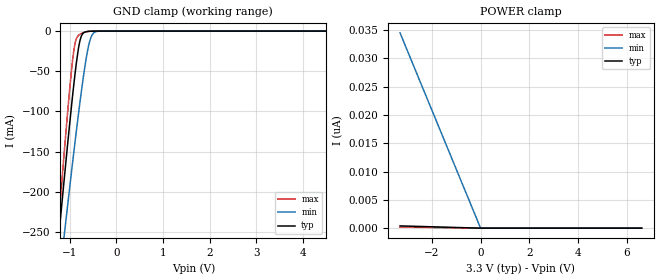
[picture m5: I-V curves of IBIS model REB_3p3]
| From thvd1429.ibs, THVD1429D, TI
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|   REB_3p3 Model
[Model]   REB_3p3
Model_type   Input
Vinl = 0.8
Vinh = 2
|   typ   min   max
C_comp   3.662pF   3.174pF   4.146pF
| Where Nom  PVT is Nominal Process, 3.3V, 25C
|   Fast PVT is Strong Process,  3.6V, -40C
|   Slow PVT is Weak Process,   3.0V, 150C
[Voltage Range]   3.3   3   3.6
|Junction Temperature
[Temperature Range]   25   150   -40
[Power Clamp Reference]   3.3   3   3.6
[GND Clamp Reference]   0   0   0
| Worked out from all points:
|   GND clamp passes 1 mA (typ) near -0.66 V on its own axis
[GND Clamp]
|   Voltage   I(typ)   I(min)   I(max)
-3.3V     -1.586A    -1.429A    -1.817A
-1.379V   -345.3mA   -390.1mA   -341.4mA
-1.221V   -246.5mA   -307.1mA   -224.3mA
-1.112V   -180.1mA   -250.8mA   -146.3mA
-993.3mV  -110.3mA   -190.5mA   -66.91mA
-914.1mV  -66.85mA   -151.2mA   -24.69mA
-874.5mV  -47.04mA   -132mA     -12.26mA
-815.1mV  -21.99mA   -103.9mA   -5.44mA
-726mV    -3.556mA   -64.31mA   -2.32mA
-567.6mV  -217.4uA   -11.67mA   -218.3uA
-399.3mV  -10.3uA    -273.4uA   -6.968uA
6.6V      0A         0A         0A
[POWER Clamp]
|   Voltage   I(typ)   I(min)   I(max)
-3.3V     400.5pA    34.52nA    192pA
0V        0A         0A         0A
6.6V      0A         0A         0A
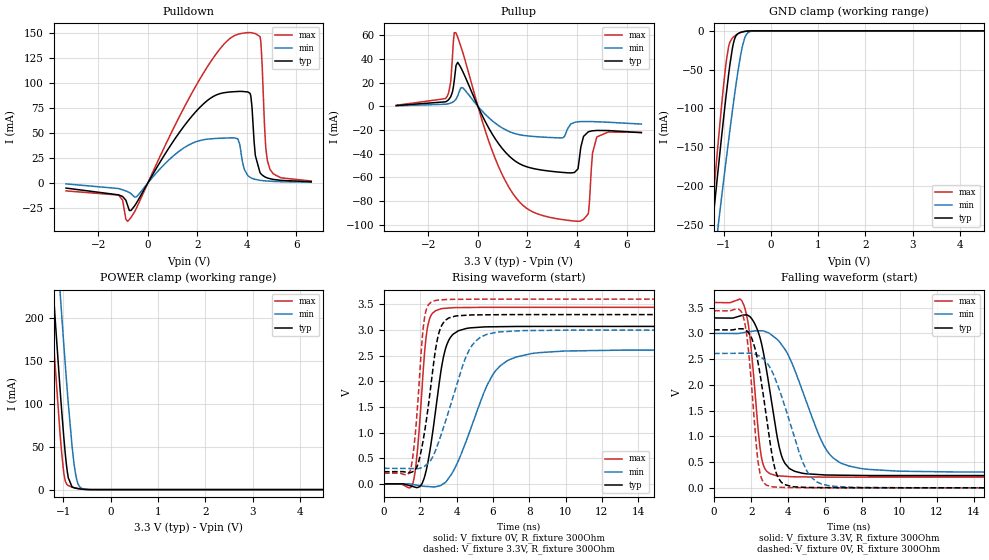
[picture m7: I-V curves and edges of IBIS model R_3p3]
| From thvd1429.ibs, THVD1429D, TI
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|   R_3p3 Model
[Model]   R_3p3
Model_type   3-state
Polarity   Non-Inverting
Vmeas = 1.65
Vref = 0
Cref = 2pF
Rref = 100000
|   typ   min   max
C_comp   4.739pF   4.609pF   4.805pF
| Where Nom  PVT is Nominal Process, 3.3V, 25C
|   Fast PVT is Strong Process,  3.6V, -40C
|   Slow PVT is Weak Process,   3.0V, 150C
[Voltage Range]   3.3   3   3.6
|Junction Temperature
[Temperature Range]   25   150   -40
[Pullup Reference]   3.3   3   3.6
[Pulldown Reference]   0   0   0
[Power Clamp Reference]   3.3   3   3.6
[GND Clamp Reference]   0   0   0
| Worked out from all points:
|   slope of the pulldown table from 0 to 0.495 V, typ, clamps not added: 23.7 ohm
|   slope of the pullup table from 0 to 0.495 V, typ, clamps not added: 24.1 ohm
|   GND clamp passes 1 mA (typ) near -0.58 V on its own axis
|   POWER clamp passes 1 mA (typ) near -0.67 V on its own axis
|   falling waveform, V_fixture 3.3V, R_fixture 300Ohm: 20-80 % time 853ps typ, 1.74ns min, 506ps max; typ from 3.3 V to 0.237 V
|   rising waveform, V_fixture 0V, R_fixture 300Ohm: 20-80 % time 751ps typ, 1.75ns min, 436ps max; typ from 0 V to 3.07 V
|   rising waveform, V_fixture 3.3V, R_fixture 300Ohm: 20-80 % time 714ps typ, 1.46ns min, 427ps max; typ from 0.237 V to 3.3 V
|   falling waveform, V_fixture 0V, R_fixture 300Ohm: 20-80 % time 781ps typ, 1.43ns min, 484ps max; typ from 3.07 V to 0 V
[Pulldown]
|   Voltage   I(typ)   I(min)   I(max)
-3.3V     -5.004mA   -808.9uA   -7.788mA
-1.191V   -11.72mA   -5.429mA   -11.96mA
-815.1mV  -22.29mA   -8.553mA   -38.1mA
2.373V    81.63mA    43.65mA    114.7mA
3.62V     91.29mA    44.25mA    148.2mA
4.046V    90.8mA     7.35mA     150mA
4.165V    85.92mA    5.258mA    149.9mA
4.343V    27.4mA     3.665mA    149mA
4.541V    10.13mA    2.745mA    145mA
4.759V    5.819mA    2.159mA    37.1mA
4.927V    4.383mA    1.859mA    14.12mA
6.6V      1.371mA    840.4uA    2.04mA
[GND Clamp]
|   Voltage   I(typ)   I(min)   I(max)
-3.3V     -1.553A    -1.424A    -1.755A
-1.379V   -339.1mA   -389.3mA   -331.1mA
-1.221V   -242.6mA   -306.6mA   -218.2mA
-1.112V   -177.7mA   -250.6mA   -143mA
-993.3mV  -109.4mA   -190.5mA   -66.79mA
-894.3mV  -57.17mA   -141.8mA   -20.64mA
-815.1mV  -23.4mA    -104.4mA   -9.505mA
-775.5mV  -12.37mA   -86.35mA   -7.293mA
-646.8mV  -2.133mA   -34.28mA   -2.531mA
-528mV    -536.6uA   -5.945mA   -570.7uA
-359.7mV  -25.1uA    -169uA     -14.98uA
6.6V      0A         0A         0A
[Pullup]
|   Voltage   I(typ)   I(min)   I(max)
-3.3V     632.8uA    409.7uA    833.3uA
-1.29V    4.001mA    1.824mA    6.974mA
-1.102V   7.96mA     2.751mA    20.36mA
-953.7mV  22.11mA    4.47mA     62.39mA
-884.4mV  34.56mA    6.104mA    62.1mA
-617.1mV  29.65mA    15.65mA    45.87mA
1.264V    -42.14mA   -21.34mA   -68.96mA
3.897V    -56.01mA   -13.6mA    -97.09mA
4.452V    -21.69mA   -12.87mA   -91.02mA
4.63V     -20.73mA   -12.96mA   -39.26mA
4.808V    -20.42mA   -13.08mA   -25.87mA
6.6V      -22.29mA   -15.03mA   -22.07mA
[POWER Clamp]
|   Voltage   I(typ)   I(min)   I(max)
-3.3V     2.079A     2.185A     2.031A
-1.449V   432.3mA    547.8mA    378.6mA
-1.251V   263.9mA    379.9mA    209.6mA
-1.221V   239.2mA    355.2mA    184.9mA
-1.191V   214.8mA    330.6mA    160.5mA
-1.063V   113mA      226.2mA    61.48mA
-983.4mV  57.32mA    164.8mA    17.27mA
-894.3mV  13.78mA    100.3mA    4.716mA
-805.2mV  2.832mA    45.77mA    2.883mA
-735.9mV  1.584mA    16.99mA    1.897mA
-567.6mV  338.4uA    707.4uA    328uA
6.6V      0A         0A         0A
[Ramp]
R_load = 300
|   typ   min   max
dV/dt_r   1.84126/7.51035e-10   1.56567/1.74295e-09   2.06375/4.34792e-10
dV/dt_f   1.83723/8.51106e-10   1.6172/1.73394e-09   2.0352/5.05101e-10
[Falling Waveform]
V_fixture = 3.3V
V_fixture_min = 3V
V_fixture_max = 3.6V
R_fixture = 300Ohm
C_fixture = 0F
|   Time   V(typ)   V(min)   V(max)
0s        3.3V       3V         3.599V
1.607ns   3.356V     3.015V     3.548V
1.939ns   3.323V     3.034V     2.915V
2.546ns   2.819V     3.052V     610.5mV
3.307ns   1.201V     2.911V     242.5mV
3.664ns   596.3mV    2.769V     229.1mV
4.097ns   368mV      2.502V     218.9mV
6.083ns   249.7mV    722.2mV    208.6mV
7.879ns   241.6mV    379mV      208.6mV
50ns      237.5mV    304.3mV    207.4mV
[Rising Waveform]
V_fixture = 0V
V_fixture_min = 0V
V_fixture_max = 0V
R_fixture = 300Ohm
C_fixture = 0F
|   Time   V(typ)   V(min)   V(max)
0s        475.4uV    423.7uV    533uV
1.579ns   -49.68mV   -10.14mV   -6.644mV
1.847ns   -70.1mV    -25.79mV   661.4mV
2.372ns   336.2mV    -49.89mV   2.993V
3.123ns   2.16V      -31.57mV   3.41V
3.416ns   2.663V     42.87mV    3.422V
3.814ns   2.917V     246.7mV    3.432V
6.083ns   3.061V     2.172V     3.439V
8.107ns   3.068V     2.538V     3.439V
50ns      3.069V     2.61V      3.44V
[Rising Waveform]
V_fixture = 3.3V
V_fixture_min = 3V
V_fixture_max = 3.6V
R_fixture = 300Ohm
C_fixture = 0F
|   Time   V(typ)   V(min)   V(max)
0s        237.5mV    304.3mV    207.4mV
1.467ns   220.9mV    300.1mV    281mV
1.746ns   289mV      299.3mV    1.05V
2.21ns    957mV      338.2mV    3.178V
2.428ns   1.479V     401.5mV    3.477V
2.846ns   2.63V      657.9mV    3.574V
3.37ns    3.184V     1.199V     3.59V
4.679ns   3.288V     2.599V     3.597V
6.193ns   3.296V     2.953V     3.599V
50ns      3.3V       3V         3.599V
[Falling Waveform]
|Gnd
V_fixture = 0V
V_fixture_min = 0V
V_fixture_max = 0V
R_fixture = 300Ohm
C_fixture = 0F
|   Time   V(typ)   V(min)   V(max)
0s        3.069V     2.61V      3.44V
1.553ns   3.087V     2.614V     3.345V
1.847ns   3.015V     2.615V     2.695V
2.288ns   2.582V     2.584V     783.8mV
2.428ns   2.316V     2.562V     373.5mV
3.064ns   777.2mV    2.304V     24.39mV
3.613ns   114.7mV    1.806V     10.56mV
4.946ns   9.975mV    367.5mV    3.634mV
6.301ns   4.702mV    36.41mV    1.367mV
50ns      475.5uV    423.8uV    533.1uV
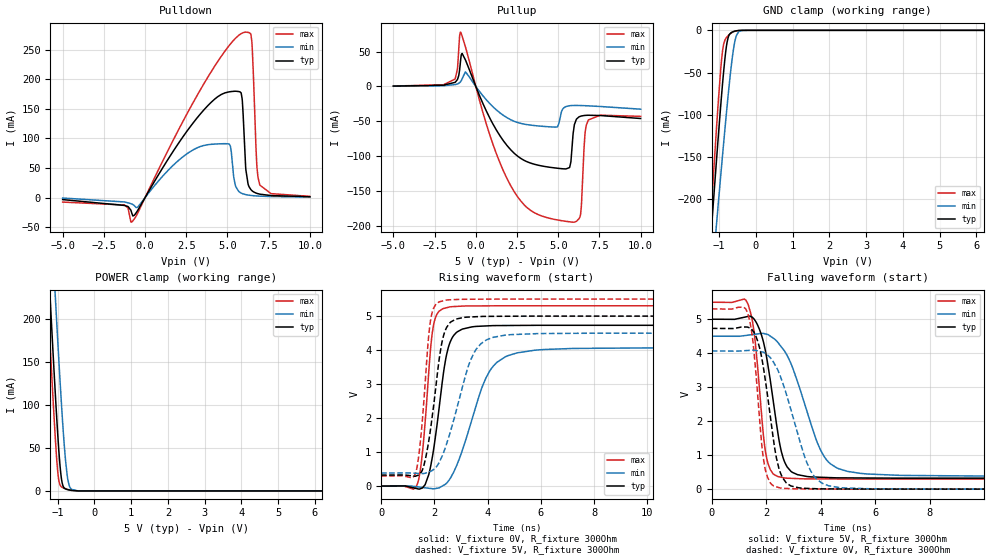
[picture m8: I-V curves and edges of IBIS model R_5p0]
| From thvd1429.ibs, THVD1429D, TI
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|   R_5p0 Model
[Model]   R_5p0
Model_type   3-state
Polarity   Non-Inverting
Vmeas = 2.5
Vref = 0
Cref = 2pF
Rref = 100000
|   typ   min   max
C_comp   4.463pF   4.322pF   4.525pF
| Where Nom  PVT is Nominal Process, 5.0V, 25C
|   Fast PVT is Strong Process,  5.5V, -40C
|   Slow PVT is Weak Process,   4.5V, 150C
[Voltage Range]   5   4.5   5.5
|Junction Temperature
[Temperature Range]   25   150   -40
[Pullup Reference]   5   4.5   5.5
[Pulldown Reference]   0   0   0
[Power Clamp Reference]   5   4.5   5.5
[GND Clamp Reference]   0   0   0
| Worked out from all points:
|   slope of the pulldown table from 0 to 0.75 V, typ, clamps not added: 21 ohm
|   slope of the pullup table from 0 to 0.75 V, typ, clamps not added: 18.5 ohm
|   GND clamp passes 1 mA (typ) near -0.58 V on its own axis
|   POWER clamp passes 1 mA (typ) near -0.67 V on its own axis
|   falling waveform, V_fixture 5V, R_fixture 300Ohm: 20-80 % time 543ps typ, 1.05ns min, 354ps max; typ from 5 V to 0.323 V
|   rising waveform, V_fixture 0V, R_fixture 300Ohm: 20-80 % time 493ps typ, 1.04ns min, 322ps max; typ from 0.001 V to 4.73 V
|   rising waveform, V_fixture 5V, R_fixture 300Ohm: 20-80 % time 472ps typ, 904ps min, 315ps max; typ from 0.323 V to 5 V
|   falling waveform, V_fixture 0V, R_fixture 300Ohm: 20-80 % time 516ps typ, 928ps min, 345ps max; typ from 4.73 V to 0.001 V
[Pulldown]
|   Voltage   I(typ)   I(min)   I(max)
-5V       -3.272mA   -664.2uA   -7.474mA
-1.25V    -13.17mA   -7.255mA   -12.42mA
-815mV    -25.38mA   -10.68mA   -41.21mA
2.74V     119.6mA    77.67mA    151.5mA
4.84V     176.7mA    91.07mA    247mA
5.17V     178.8mA    87.21mA    259mA
5.83V     176.7mA    7.735mA    276.7mA
6.1V      52.61mA    5.157mA    279.4mA
6.475V    11.97mA    3.537mA    264.7mA
6.775V    7.308mA    2.84mA     57.1mA
6.97V     5.846mA    2.522mA    21mA
10V       1.556mA    1.006mA    2.167mA
[GND Clamp]
|   Voltage   I(typ)   I(min)   I(max)
-5V       -2.641A    -2.352A    -3.031A
-1.235V   -251mA     -313.8mA   -228mA
-1.13V    -188.2mA   -259.7mA   -155.1mA
-1.07V    -153mA     -229.1mA   -114.9mA
-920mV    -70mA      -154.3mA   -29.31mA
-875mV    -47.91mA   -132.5mA   -16.1mA
-785mV    -14.5mA    -90.57mA   -7.764mA
-725mV    -5.385mA   -64.41mA   -5.067mA
-620mV    -1.605mA   -25.54mA   -1.903mA
-530mV    -550.4uA   -6.168mA   -587.7uA
-365mV    -28.14uA   -188uA     -17.18uA
10V       0A         0A         0A
[Pullup]
|   Voltage   I(typ)   I(min)   I(max)
-5V       470.4uA    327uA      589.4uA
-1.25V    5.856mA    2.602mA    10.69mA
-920mV    37.97mA    6.899mA    77.76mA
850mV     -45.44mA   -24.68mA   -69.72mA
2.125V    -91.09mA   -47.86mA   -142.8mA
4.915V    -117.3mA   -58.18mA   -191.5mA
5.77V     -108.2mA   -27.52mA   -194.5mA
5.98V     -54.86mA   -27.32mA   -194.8mA
6.355V    -42.8mA    -27.42mA   -183.9mA
6.625V    -41.62mA   -27.65mA   -67.69mA
6.82V     -41.37mA   -27.86mA   -48.56mA
10V       -46.04mA   -32.66mA   -42.97mA
[POWER Clamp]
|   Voltage   I(typ)   I(min)   I(max)
-5V       3.611A     3.713A     3.566A
-1.415V   403.3mA    518.9mA    349.4mA
-1.25V    263.3mA    379.3mA    208.9mA
-1.175V   201.4mA    317.1mA    147.1mA
-1.07V    118.5mA    232mA      66.29mA
-995mV    64.68mA    173.5mA    21.54mA
-890mV    12.46mA    97.34mA    4.562mA
-815mV    3.161mA    50.92mA    3.028mA
-740mV    1.625mA    18.16mA    1.942mA
-635mV    713.9uA    2.306mA    796uA
-455mV    44.97uA    127.9uA    26.23uA
10V       0A         0A         0A
[Ramp]
R_load = 300
|   typ   min   max
dV/dt_r   2.83718/4.93393e-10   2.43849/1.04154e-09   3.18127/3.2074e-10
dV/dt_f   2.80555/5.42926e-10   2.46915/1.04462e-09   3.12173/3.53502e-10
[Falling Waveform]
V_fixture = 5V
V_fixture_min = 4.5V
V_fixture_max = 5.5V
R_fixture = 300Ohm
C_fixture = 0F
|   Time   V(typ)   V(min)   V(max)
0s        4.999V     4.499V     5.499V
1.323ns   5.08V      4.529V     5.458V
1.57ns    4.985V     4.555V     4.524V
1.889ns   4.361V     4.584V     1.656V
2.024ns   3.833V     4.556V     885.4mV
2.464ns   1.474V     4.28V      366.8mV
2.666ns   821.8mV    4.07V      332.2mV
4.149ns   346.3mV    934mV      301.4mV
5.593ns   329.6mV    455.4mV    297.5mV
50ns      323.3mV    384.1mV    296.3mV
[Rising Waveform]
V_fixture = 0V
V_fixture_min = 0V
V_fixture_max = 0V
R_fixture = 300Ohm
C_fixture = 0F
|   Time   V(typ)   V(min)   V(max)
0s        730.7uV    646.7uV    820.7uV
1.368ns   -78.39mV   -22.15mV   66.04mV
1.57ns    -37.95mV   -41.87mV   1.097V
1.85ns    535.1mV    -69.31mV   3.95V
1.964ns   1.027V     -78.38mV   4.7V
2.377ns   3.495V     35.71mV    5.227V
2.568ns   4.176V     190.5mV    5.267V
4.08ns    4.714V     3.382V     5.3V
5.757ns   4.727V     3.994V     5.302V
50ns      4.729V     4.065V     5.303V
[Rising Waveform]
V_fixture = 5V
V_fixture_min = 4.5V
V_fixture_max = 5.5V
R_fixture = 300Ohm
C_fixture = 0F
|   Time   V(typ)   V(min)   V(max)
0s        323.3mV    384.1mV    296.3mV
1.303ns   293.5mV    378mV      388.2mV
1.503ns   402mV      370.6mV    1.506V
1.77ns    1.218V     407.1mV    4.242V
1.871ns   1.737V     436.5mV    4.927V
2.214ns   3.898V     745.8mV    5.423V
2.424ns   4.597V     1.151V     5.467V
3.503ns   4.978V     3.934V     5.494V
4.765ns   4.994V     4.446V     5.498V
50ns      4.999V     4.499V     5.499V
[Falling Waveform]
|Gnd
V_fixture = 0V
V_fixture_min = 0V
V_fixture_max = 0V
R_fixture = 300Ohm
C_fixture = 0F
|   Time   V(typ)   V(min)   V(max)
0s        4.729V     4.065V     5.303V
1.303ns   4.769V     4.079V     5.211V
1.503ns   4.667V     4.089V     4.405V
1.835ns   3.865V     4.04V      1.319V
1.944ns   3.334V     4.009V     666.5mV
2.321ns   1.163V     3.66V      81.43mV
2.523ns   476.2mV    3.311V     33.84mV
3.63ns    19.7mV     544.5mV    6.575mV
4.765ns   6.909mV    43mV       2.61mV
50ns      730.7uV    646.8uV    820.8uV
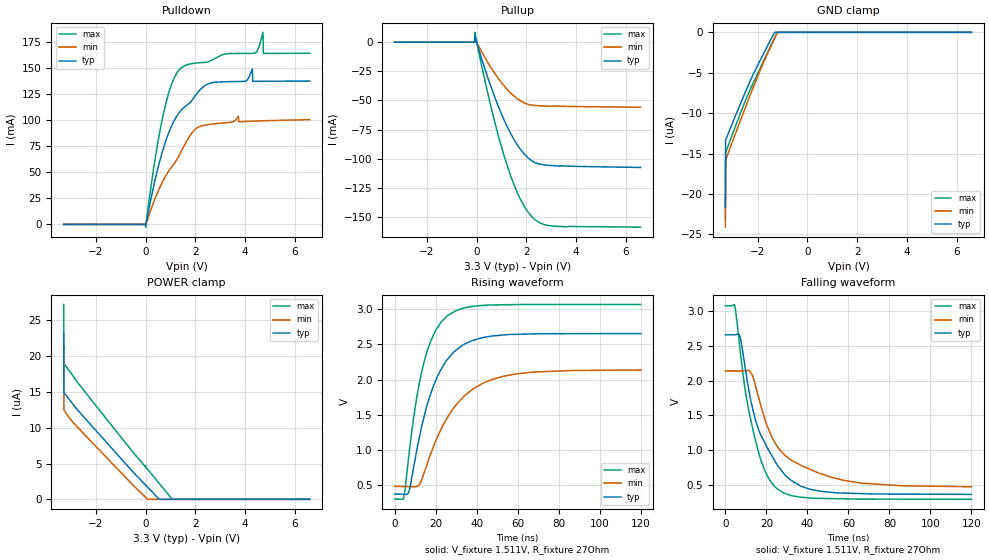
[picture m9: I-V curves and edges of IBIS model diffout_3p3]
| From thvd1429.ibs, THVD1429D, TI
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|   diffout_3p3 Model
[Model]   diffout_3p3
Model_type   I/O
Polarity   Non-Inverting
Enable   Active-High
Vinl = 0.8
Vinh = 2
Vmeas = 1.5107
Vref = 1.5107
Cref = 50pF
Rref = 27
|   typ   min   max
C_comp   801.014pF   801.014pF   801.014pF
| Where Nom  PVT is Nominal Process, 3.3V, 25C
|   Fast PVT is Strong Process,  3.6V, -40C
|   Slow PVT is Weak Process,   3.0V, 150C
[Voltage Range]   3.3   3   3.6
|Junction Temperature
[Temperature Range]   25   150   -40
[Pullup Reference]   3.3   3   3.6
[Pulldown Reference]   -0   -0   0
[Power Clamp Reference]   3.3   3   3.6
[GND Clamp Reference]   0   0   0
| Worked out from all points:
|   slope of the pulldown table from 0 to 0.495 V, typ, clamps not added: 9.09 ohm
|   slope of the pullup table from 0 to 0.495 V, typ, clamps not added: 14.8 ohm
|   falling waveform, V_fixture 1.511V, R_fixture 27Ohm: 20-80 % time 15ns typ, 19.5ns min, 10.5ns max; typ from 2.65 V to 0.368 V
|   rising waveform, V_fixture 1.511V, R_fixture 27Ohm: 20-80 % time 14ns typ, 19.6ns min, 10.5ns max; typ from 0.368 V to 2.65 V
[Pulldown]
|   Voltage   I(typ)   I(min)   I(max)
-3.3V     -7.88uA    -6.87uA    -8.778uA
-3.3mV    -4.104uA   -4.239uA   -2.643mA
729.3mV   74.57mA    43.42mA    108.2mA
1.452V    110.4mA    71.31mA    151mA
2.234V    130.6mA    94.63mA    155.6mA
4.036V    137.9mA    98.98mA    164.4mA
4.293V    149.5mA    99.25mA    164.5mA
4.303V    138mA      99.26mA    164.5mA
4.392V    137.6mA    99.35mA    164.7mA
4.719V    137.6mA    99.64mA    184.7mA
4.739V    137.6mA    99.66mA    164.4mA
6.6V      137.8mA    100.8mA    164.5mA
[GND Clamp]
|   Voltage   I(typ)   I(min)   I(max)
-3.3V     -21.56uA   -24.1uA    -23.13uA
-3.29V    -13.33uA   -15.86uA   -14.9uA
-2.993V   -11.06uA   -13.33uA   -12.43uA
-2.548V   -7.766uA   -9.732uA   -8.875uA
-2.122V   -4.835uA   -6.386uA   -5.881uA
-1.756V   -2.588uA   -3.671uA   -3.499uA
-1.33V    -33.8nA    -820.1nA   -740.1nA
-1.211V   0A         -47.18nA   -20.42nA
6.6V      0A         0A         0A
[Pullup]
|   Voltage   I(typ)   I(min)   I(max)
-3.3V     95.64uA    90.85uA    109.2uA
-82.5mV   76.14uA    64.33uA    85.74uA
-72.6mV   75.25uA    63.41uA    8.584mA
-62.7mV   5.569mA    62.48uA    7.46mA
-42.9mV   3.549mA    2.034mA    5.359mA
570.9mV   -37.69mA   -21.45mA   -54.64mA
1.185V    -70.33mA   -39.34mA   -102.8mA
1.769V    -92.11mA   -50.3mA    -135.2mA
2.095V    -99.84mA   -53.45mA   -146.7mA
2.373V    -103.7mA   -54.34mA   -152.8mA
3.204V    -106.3mA   -54.88mA   -158.2mA
6.6V      -107.6mA   -55.87mA   -159mA
[POWER Clamp]
|   Voltage   I(typ)   I(min)   I(max)
-3.3V     23.13uA    20.76uA    27.21uA
-3.29V    14.87uA    12.48uA    18.95uA
-3.102V   14.08uA    11.53uA    18.07uA
-2.409V   11.18uA    8.854uA    14.86uA
-399.3mV  3.4uA      1.607uA    6.1uA
-13.2mV   2.026uA    297.5nA    4.56uA
-3.3mV    1.994uA    265nA      4.667uA
6.6mV     1.962uA    232.7nA    4.417uA
66mV      1.727uA    13.47nA    4.209uA
531.3mV   25.87nA    0A         2.277uA
1.066V    0A         0A         4.584nA
6.6V      0A         0A         0A
[Ramp]
R_load = 27
|   typ   min   max
dV/dt_r   1.37208/1.39066e-08   0.995048/1.95025e-08   1.6634/1.04912e-08
dV/dt_f   1.37218/1.49177e-08   0.995136/1.9355e-08   1.66437/1.05253e-08
[Falling Waveform]
V_fixture = 1.511V
V_fixture_min = 1.305V
V_fixture_max = 1.683V
R_fixture = 27Ohm
C_fixture = 0F
|   Time   V(typ)   V(min)   V(max)
0s        2.655V     2.136V     3.071V
4.623ns   2.656V     2.136V     3.066V
7.309ns   2.61V      2.137V     2.408V
9.582ns   2.2V       2.141V     1.882V
12.16ns   1.749V     2.129V     1.467V
17.89ns   1.183V     1.579V     811.6mV
25.28ns   790.2mV    1.058V     447.7mV
37.01ns   484.8mV    782.8mV    327.6mV
57.6ns    387mV      570.5mV    304.7mV
120ns     368.4mV    477.5mV    297.5mV
[Rising Waveform]
V_fixture = 1.511V
V_fixture_min = 1.305V
V_fixture_max = 1.683V
R_fixture = 27Ohm
C_fixture = 0F
|   Time   V(typ)   V(min)   V(max)
0s        368.4mV    477.7mV    297.4mV
4.556ns   364.4mV    475.1mV    324.1mV
6.927ns   396.1mV    473.7mV    905.2mV
10.41ns   924.5mV    471.8mV    1.668V
15.5ns    1.593V     762.5mV    2.365V
20.11ns   1.99V      1.127V     2.703V
26.15ns   2.299V     1.476V     2.92V
38.61ns   2.561V     1.873V     3.045V
53.19ns   2.636V     2.047V     3.066V
120ns     2.655V     2.136V     3.07V
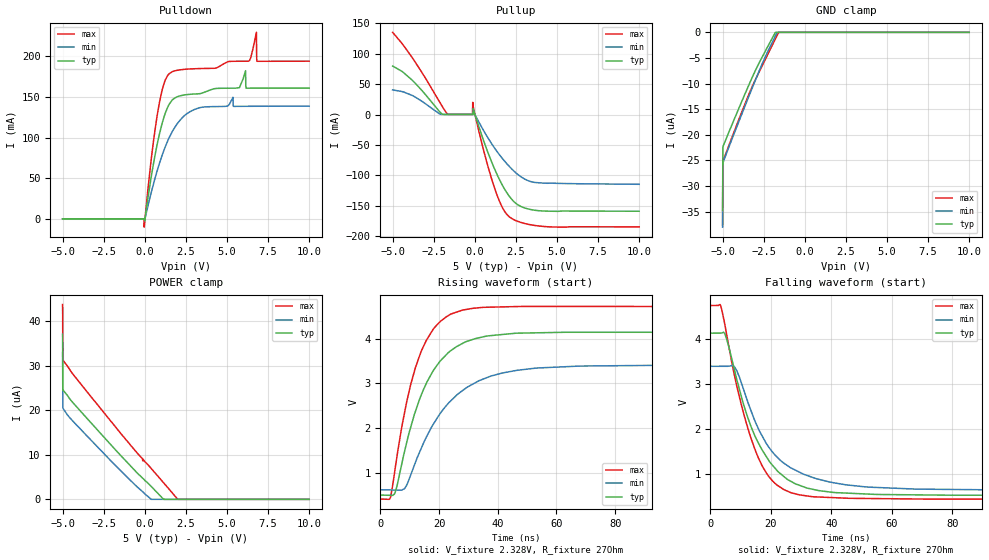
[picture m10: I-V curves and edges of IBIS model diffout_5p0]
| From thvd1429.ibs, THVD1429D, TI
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|   diffout_5p0 Model
[Model]   diffout_5p0
Model_type   I/O
Polarity   Non-Inverting
Enable   Active-High
Vinl = 0.8
Vinh = 2
Vmeas = 2.3275
Vref = 2.3275
Cref = 50pF
Rref = 27
|   typ   min   max
C_comp   801.023pF   801.023pF   801.023pF
| Where Nom  PVT is Nominal Process, 5.0V, 25C
|   Fast PVT is Strong Process,  5.5V, -40C
|   Slow PVT is Weak Process,   4.5V, 150C
[Voltage Range]   5   4.5   5.5
|Junction Temperature
[Temperature Range]   25   150   -40
[Pullup Reference]   5   4.5   5.5
[Pulldown Reference]   -0   -0   0
[Power Clamp Reference]   5   4.5   5.5
[GND Clamp Reference]   0   0   0
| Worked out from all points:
|   slope of the pulldown table from 0 to 0.75 V, typ, clamps not added: 8.06 ohm
|   slope of the pullup table from 0 to 0.75 V, typ, clamps not added: 12.6 ohm
|   falling waveform, V_fixture 2.328V, R_fixture 27Ohm: 20-80 % time 12.3ns typ, 14.2ns min, 10.3ns max; typ from 4.14 V to 0.516 V
|   rising waveform, V_fixture 2.328V, R_fixture 27Ohm: 20-80 % time 12ns typ, 16.5ns min, 9.69ns max; typ from 0.517 V to 4.14 V
[Pulldown]
|   Voltage   I(typ)   I(min)   I(max)
-5V       -7.974uA   -6.947uA   -8.847uA
-35mV     -2.816uA   -3.805uA   -10.18mA
805mV     96.63mA    62.68mA    133.4mA
1.66V     146mA      107mA      180.9mA
3.28V     153.9mA    136.5mA    184.9mA
5.755V    161.4mA    138.5mA    193.9mA
6.13V     182.3mA    138.5mA    194mA
6.16V     160.8mA    138.5mA    194mA
6.295V    160.8mA    138.5mA    194mA
6.79V     160.8mA    138.5mA    229.5mA
6.82V     160.8mA    138.5mA    193.9mA
10V       160.9mA    138.7mA    194mA
[GND Clamp]
|   Voltage   I(typ)   I(min)   I(max)
-5V       -34.79uA   -38uA      -37.66uA
-4.985V   -22.33uA   -25.53uA   -25.19uA
-3.68V    -12.33uA   -14.72uA   -14.29uA
-3.29V    -9.455uA   -11.59uA   -11.24uA
-2.975V   -7.24uA    -9.088uA   -9.044uA
-2.525V   -4.41uA    -5.66uA    -6.084uA
-1.79V    -8.794nA   -710.9nA   -1.3uA
-1.685V   0A         -22.33nA   -628.6nA
-1.565V   0A         0A         0A
10V       0A         0A         0A
[Pullup]
|   Voltage   I(typ)   I(min)   I(max)
-5V       79.67mA    40.36mA    135.1mA
-3.68V    52.97mA    29.51mA    88.43mA
-2.03V    1.52mA     167.4uA    15.62mA
-1.715V   103.1uA    93.74uA    2.186mA
-140mV    85.78uA    71.98uA    97.4uA
-125mV    84.4uA     70.61uA    20.08mA
-95mV     9.704mA    67.83uA    12.48mA
1.09V     -82.36mA   -50.68mA   -111.7mA
1.615V    -113.1mA   -70.2mA    -149.5mA
2.08V     -133.7mA   -84.82mA   -167.7mA
3.595V    -157.2mA   -111.4mA   -182.2mA
10V       -159mA     -114.7mA   -184.7mA
[POWER Clamp]
|   Voltage   I(typ)   I(min)   I(max)
-5V       37.03uA    32.98uA    43.69uA
-4.985V   24.55uA    20.47uA    31.23uA
-4.67V    23.09uA    18.76uA    29.68uA
-4.34V    21.54uA    17.41uA    27.92uA
-1.595V   10.34uA    6.89uA     15.37uA
-140mV    4.782uA    1.727uA    9.099uA
-125mV    4.728uA    1.675uA    8.656uA
-110mV    4.674uA    1.624uA    8.978uA
370mV     2.964uA    50.79nA    7.01uA
1.135V    35.33nA    0A         3.743uA
2.005V    0A         0A         1.112nA
10V       0A         0A         0A
[Ramp]
R_load = 27
|   typ   min   max
dV/dt_r   2.17414/1.19781e-08   1.6588/1.6392e-08   2.59823/9.66875e-09
dV/dt_f   2.17415/1.22509e-08   1.65878/1.40682e-08   2.59823/1.03092e-08
[Falling Waveform]
V_fixture = 2.328V
V_fixture_min = 2.017V
V_fixture_max = 2.591V
R_fixture = 27Ohm
C_fixture = 0F
|   Time   V(typ)   V(min)   V(max)
0s        4.14V      3.4V       4.758V
3.211ns   4.141V     3.4V       4.781V
4.76ns    4.136V     3.4V       4.351V
7.937ns   3.332V     3.393V     3.212V
10.47ns   2.673V     2.989V     2.483V
17.24ns   1.519V     1.831V     1.164V
24.29ns   937.9mV    1.237V     645.9mV
34.29ns   644.6mV    905.5mV    483.1mV
97.29ns   519.4mV    636.5mV    432.3mV
1us       516.5mV    635mV      427.2mV
[Rising Waveform]
V_fixture = 2.328V
V_fixture_min = 2.017V
V_fixture_max = 2.591V
R_fixture = 27Ohm
C_fixture = 0F
|   Time   V(typ)   V(min)   V(max)
0s        516.5mV    634.9mV    427.2mV
3.437ns   510.4mV    630mV      456.8mV
4.961ns   556.4mV    627.8mV    1.059V
8.241ns   1.48V      659.5mV    2.341V
10.54ns   2.066V     994mV      3.02V
13.78ns   2.715V     1.529V     3.689V
17.88ns   3.268V     2.073V     4.192V
29.57ns   3.938V     2.917V     4.651V
48.08ns   4.121V     3.304V     4.714V
15us      4.14V      3.4V       4.758V
